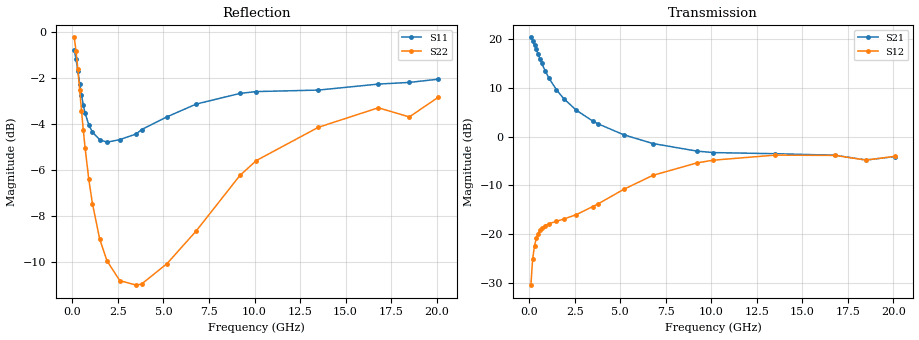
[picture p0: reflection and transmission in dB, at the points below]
!  Infineon Technologies AG
! BFR380L3 , PF131585-7, No.6, Th 09.10.01, soldered on pcb-board, measured with PP GSG850
!  Vce=2.5 V,  Ic=3.0 mA
! Common Emitter S-Parameters:  15. November 2001
#  GHz  S  MA  R  50
! f  S11  S21  S12  S22
! GHz  Mag  Ang  Mag  Ang  Mag  Ang  Mag  Ang
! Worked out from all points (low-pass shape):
!   201 points, 100 MHz to 20.1 GHz, reference 50 ohm
!   highest |S21| = 20.31 dB at 100 MHz (marker M1); lowest = -4.8 dB at 18.5 GHz (marker M2)
!   |S21| within 3 dB of the highest: start of sweep to 453.6 MHz
!   lowest |S11| = -4.8 dB at 1.9 GHz (marker M3), VSWR 3.71, Z = 13.5 - j3.3 ohm
!   |S11| at or under -10 dB: nowhere
!   |S22| runs from -11.1 to -0.2 dB; largest |S21 - S12| = 10
!   S11 on the Smith chart (normalised r, x): 100 MHz: 1.19, -4.90; 400 MHz: 0.33, -1.23; 1.1 GHz: 0.28, -0.35; 3.8 GHz: 0.26, +0.28; 9.2 GHz: 0.34, +1.07; 20.1 GHz: 0.98, +2.55
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0.1  0.9137 -21.8  10.36 165.3  0.03023 79.2  0.9723 -12.3
0.2  0.8721 -41.8  9.558 152.0  0.0565 67.3  0.9102 -23.3
0.3  0.8221 -60.1  8.695 140.4  0.07671 58.7  0.8284 -32.4
0.4  0.7716 -75.7  7.794 130.7  0.09122 51.8  0.747 -39.7
0.5  0.7291 -89.0  6.961 122.6  0.1019 46.6  0.6738 -45.4
0.6  0.6922 -100.5  6.227 116.0  0.1095 42.8  0.6108 -49.9
0.7  0.6649 -110.5  5.618 110.2  0.1153 39.8  0.5582 -53.4
0.9  0.6279 -126.5  4.641 100.9  0.1231 36.2  0.4781 -58.7
1.1  0.6052 -139.1  3.947 93.4  0.1285 34.3  0.4232 -62.7
1.5  0.5825 -157.9  3.024 81.6  0.136 33.8  0.3543 -68.7
1.9  0.5754 -171.9  2.452 72.1  0.1432 35.4  0.3177 -74.3
2.6  0.5828 169.8  1.86 58.5  0.1593 39.8  0.2878 -85.1
3.5  0.5995 151.5  1.441 43.9  0.1925 45.5  0.2813 -100.6
3.8  0.6128 146.6  1.349 39.9  0.2053 46.7  0.2828 -107.2
5.2  0.6534 125.4  1.044 23.2  0.289 46.6  0.3134 -135.1
6.8  0.6963 105.3  0.8498 9.9  0.4015 39.3  0.369 -168.1
9.2  0.7345 83.2  0.7115 -2.0  0.5372 21.8  0.4872 152.6
10.1  0.7413 76.6  0.6866 -5.3  0.5737 15.1  0.5248 140.1
13.5  0.7468 58.5  0.6687 -18.6  0.6463 -8.6  0.6198 103.5
16.8  0.7696 47.0  0.6451 -30.9  0.6425 -25.5  0.6835 79.1
18.5  0.7761 45.2  0.5762 -38.7  0.5755 -34.2  0.6529 72.9
20.1  0.7888 38.3  0.6256 -42.2  0.6288 -39.3  0.7209 61.7
